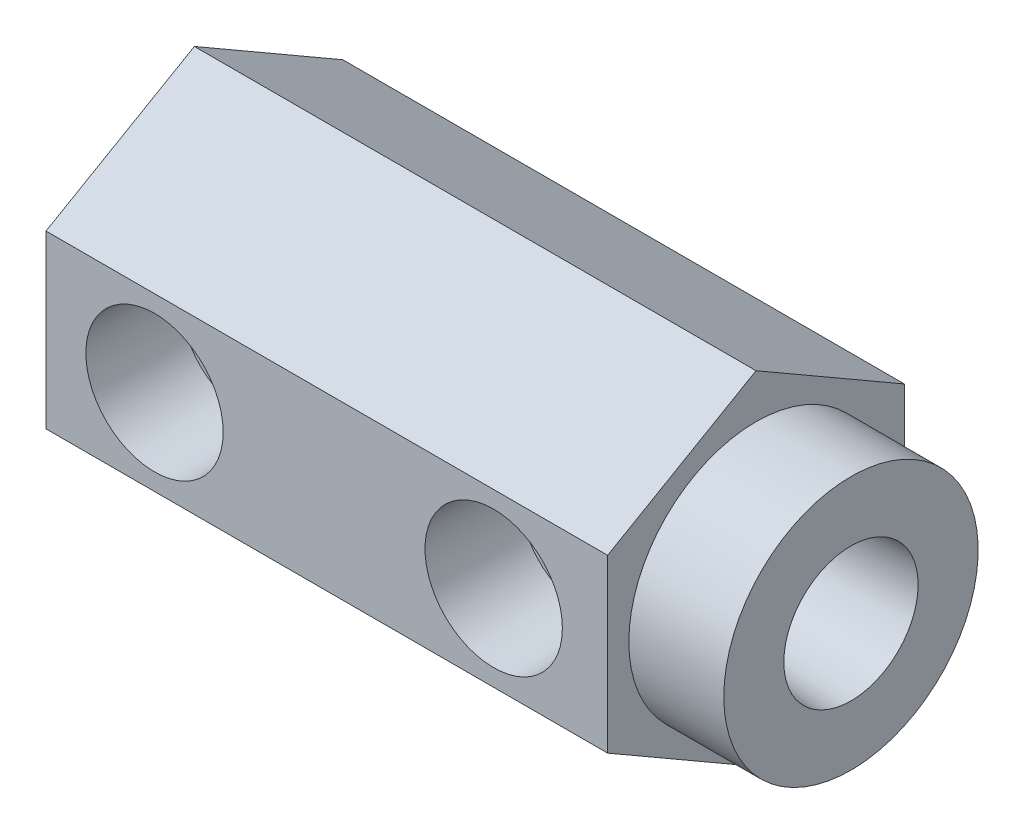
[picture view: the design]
ISO-10303-21;
HEADER;
FILE_DESCRIPTION(('STEP AP214'),'2;1');
FILE_NAME('part.step','',(''),(''),'','','');
FILE_SCHEMA(('AUTOMOTIVE_DESIGN { 1 0 10303 214 1 1 1 1 }'));
ENDSEC;
DATA;
#1=APPLICATION_CONTEXT('core data for automotive mechanical design processes');
#2=APPLICATION_PROTOCOL_DEFINITION('international standard','automotive_design',2000,#1);
#3=PRODUCT_CONTEXT('',#1,'mechanical');
#4=PRODUCT('Part','Part','',(#3));
#5=PRODUCT_RELATED_PRODUCT_CATEGORY('part','',(#4));
#6=PRODUCT_DEFINITION_FORMATION('','',#4);
#7=PRODUCT_DEFINITION_CONTEXT('part definition',#1,'design');
#8=PRODUCT_DEFINITION('design','',#6,#7);
#9=PRODUCT_DEFINITION_SHAPE('','',#8);
#10=(LENGTH_UNIT() NAMED_UNIT(*) SI_UNIT(.MILLI.,.METRE.));
#11=(NAMED_UNIT(*) PLANE_ANGLE_UNIT() SI_UNIT($,.RADIAN.));
#12=(NAMED_UNIT(*) SI_UNIT($,.STERADIAN.) SOLID_ANGLE_UNIT());
#13=UNCERTAINTY_MEASURE_WITH_UNIT(LENGTH_MEASURE(1.E-05),#10,'distance_accuracy_value','');
#14=(GEOMETRIC_REPRESENTATION_CONTEXT(3) GLOBAL_UNCERTAINTY_ASSIGNED_CONTEXT((#13)) GLOBAL_UNIT_ASSIGNED_CONTEXT((#10,
#11,#12)) REPRESENTATION_CONTEXT('',''));
#15=CARTESIAN_POINT('',(0.,0.,0.));
#16=DIRECTION('',(0.,0.,1.));
#17=DIRECTION('',(1.,0.,0.));
#18=AXIS2_PLACEMENT_3D('',#15,#16,#17);
#19=CARTESIAN_POINT('',(49.1744,0.,0.));
#20=DIRECTION('',(-1.,0.,0.));
#21=DIRECTION('',(0.,0.,1.));
#22=AXIS2_PLACEMENT_3D('',#19,#20,#21);
#23=PLANE('',#22);
#24=CARTESIAN_POINT('',(49.1744,0.,0.));
#25=DIRECTION('',(-1.,0.,0.));
#26=DIRECTION('',(0.,0.,1.));
#27=AXIS2_PLACEMENT_3D('',#24,#25,#26);
#28=CIRCLE('',#27,9.525);
#29=CARTESIAN_POINT('',(49.1744,0.,9.525));
#30=VERTEX_POINT('',#29);
#31=EDGE_CURVE('E140',#30,#30,#28,.T.);
#32=ORIENTED_EDGE('',*,*,#31,.F.);
#33=EDGE_LOOP('',(#32));
#34=FACE_BOUND('',#33,.T.);
#35=CARTESIAN_POINT('',(49.1744,0.,0.));
#36=DIRECTION('',(-1.,0.,0.));
#37=DIRECTION('',(0.,0.,1.));
#38=AXIS2_PLACEMENT_3D('',#35,#36,#37);
#39=CIRCLE('',#38,5.0292);
#40=CARTESIAN_POINT('',(49.1744,0.,5.0292));
#41=VERTEX_POINT('',#40);
#42=EDGE_CURVE('E165',#41,#41,#39,.T.);
#43=ORIENTED_EDGE('',*,*,#42,.T.);
#44=EDGE_LOOP('',(#43));
#45=FACE_BOUND('',#44,.T.);
#46=ADVANCED_FACE('F34',(#34,#45),#23,.F.);
#47=CARTESIAN_POINT('',(33.528,0.,11.1125));
#48=DIRECTION('',(0.,0.,1.));
#49=DIRECTION('',(1.,0.,0.));
#50=AXIS2_PLACEMENT_3D('',#47,#48,#49);
#51=CYLINDRICAL_SURFACE('',#50,4.2164);
#52=CARTESIAN_POINT('',(37.5572446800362,1.24226256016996,4.18846));
#53=CARTESIAN_POINT('',(37.5231998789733,1.35273524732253,4.15571145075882));
#54=CARTESIAN_POINT('',(37.4849506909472,1.46061657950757,4.11894514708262));
#55=CARTESIAN_POINT('',(37.4010204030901,1.67046449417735,4.03838194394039));
#56=CARTESIAN_POINT('',(37.3553534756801,1.77244186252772,3.99459845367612));
#57=CARTESIAN_POINT('',(37.2579636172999,1.96909195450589,3.90138657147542));
#58=CARTESIAN_POINT('',(37.2063122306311,2.06383226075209,3.85202501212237));
#59=CARTESIAN_POINT('',(37.0973370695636,2.24704879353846,3.74810382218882));
#60=CARTESIAN_POINT('',(37.040010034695,2.33552136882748,3.69354120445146));
#61=CARTESIAN_POINT('',(36.9057433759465,2.52699524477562,3.56608812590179));
#62=CARTESIAN_POINT('',(36.8274426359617,2.62823562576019,3.49198535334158));
#63=CARTESIAN_POINT('',(36.6643644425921,2.82084714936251,3.33832581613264));
#64=CARTESIAN_POINT('',(36.5795859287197,2.91221667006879,3.25876815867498));
#65=CARTESIAN_POINT('',(36.4040104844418,3.08575940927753,3.09496594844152));
#66=CARTESIAN_POINT('',(36.313183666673,3.16788058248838,3.01069851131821));
#67=CARTESIAN_POINT('',(36.1266289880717,3.32262611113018,2.83900033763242));
#68=CARTESIAN_POINT('',(36.0309017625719,3.39525169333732,2.75157001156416));
#69=CARTESIAN_POINT('',(35.8327510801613,3.53285031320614,2.57262594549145));
#70=CARTESIAN_POINT('',(35.7302251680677,3.59761324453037,2.48106457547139));
#71=CARTESIAN_POINT('',(35.5205770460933,3.7178327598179,2.29700025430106));
#72=CARTESIAN_POINT('',(35.413452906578,3.77328538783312,2.2044969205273));
#73=CARTESIAN_POINT('',(35.1946305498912,3.87490518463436,2.02052791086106));
#74=CARTESIAN_POINT('',(35.0829462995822,3.9210984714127,1.92906002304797));
#75=CARTESIAN_POINT('',(34.8537235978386,4.00442086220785,1.74949909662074));
#76=CARTESIAN_POINT('',(34.7361912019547,4.04155911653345,1.66140272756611));
#77=CARTESIAN_POINT('',(34.5288880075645,4.09683754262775,1.51866750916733));
#78=CARTESIAN_POINT('',(34.4412500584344,4.11734344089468,1.46186744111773));
#79=CARTESIAN_POINT('',(34.2602263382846,4.15335926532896,1.35613372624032));
#80=CARTESIAN_POINT('',(34.166846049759,4.16887387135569,1.30719273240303));
#81=CARTESIAN_POINT('',(34.0032271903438,4.19006857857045,1.23719318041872));
#82=CARTESIAN_POINT('',(33.9349286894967,4.19730703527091,1.21220489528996));
#83=CARTESIAN_POINT('',(33.7951867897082,4.20850549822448,1.17274151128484));
#84=CARTESIAN_POINT('',(33.7237554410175,4.21247707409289,1.15822933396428));
#85=CARTESIAN_POINT('',(33.5783648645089,4.21673052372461,1.14266473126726));
#86=CARTESIAN_POINT('',(33.5043857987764,4.21696850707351,1.14177241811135));
#87=CARTESIAN_POINT('',(33.3576831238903,4.21360126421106,1.15412545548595));
#88=CARTESIAN_POINT('',(33.2849618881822,4.20998943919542,1.16739508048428));
#89=CARTESIAN_POINT('',(33.1190041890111,4.19759986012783,1.21128529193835));
#90=CARTESIAN_POINT('',(33.0270782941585,4.187494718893,1.24623585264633));
#91=CARTESIAN_POINT('',(32.8490963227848,4.16236327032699,1.32777375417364));
#92=CARTESIAN_POINT('',(32.7630740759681,4.14731106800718,1.37442201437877));
#93=CARTESIAN_POINT('',(32.5528728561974,4.10412945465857,1.49961321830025));
#94=CARTESIAN_POINT('',(32.4317509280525,4.07325238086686,1.58224397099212));
#95=CARTESIAN_POINT('',(32.1964925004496,4.00252087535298,1.75355286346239));
#96=CARTESIAN_POINT('',(32.082370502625,3.96264855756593,1.8422428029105));
#97=CARTESIAN_POINT('',(31.8591995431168,3.87396052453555,2.02210861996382));
#98=CARTESIAN_POINT('',(31.7501633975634,3.8251236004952,2.11328994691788));
#99=CARTESIAN_POINT('',(31.5367944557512,3.71851194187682,2.29570274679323));
#100=CARTESIAN_POINT('',(31.4324577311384,3.66074485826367,2.38693411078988));
#101=CARTESIAN_POINT('',(31.2217376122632,3.5320493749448,2.57385350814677));
#102=CARTESIAN_POINT('',(31.1156451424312,3.46051807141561,2.66945656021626));
#103=CARTESIAN_POINT('',(30.9087479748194,3.30668578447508,2.85780367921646));
#104=CARTESIAN_POINT('',(30.8079452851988,3.22438075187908,2.95054665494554));
#105=CARTESIAN_POINT('',(30.6125764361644,3.04885609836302,3.13157084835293));
#106=CARTESIAN_POINT('',(30.5179955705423,2.95566377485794,3.21986246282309));
#107=CARTESIAN_POINT('',(30.3358368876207,2.7579369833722,3.39076686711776));
#108=CARTESIAN_POINT('',(30.248259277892,2.65340217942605,3.47337948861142));
#109=CARTESIAN_POINT('',(30.0468993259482,2.38706899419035,3.66401417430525));
#110=CARTESIAN_POINT('',(29.9372028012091,2.21943248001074,3.76846671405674));
#111=CARTESIAN_POINT('',(29.7890253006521,1.95153796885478,3.91000109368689));
#112=CARTESIAN_POINT('',(29.742405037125,1.85961524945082,3.95461240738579));
#113=CARTESIAN_POINT('',(29.6552306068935,1.67047982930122,4.03813946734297));
#114=CARTESIAN_POINT('',(29.6146718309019,1.57327122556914,4.07705954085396));
#115=CARTESIAN_POINT('',(29.5633807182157,1.43577933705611,4.12632709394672));
#116=CARTESIAN_POINT('',(29.5497360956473,1.3975361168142,4.13943898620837));
#117=CARTESIAN_POINT('',(29.5234701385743,1.32038947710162,4.16468855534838));
#118=CARTESIAN_POINT('',(29.510848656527,1.28148615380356,4.17682637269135));
#119=CARTESIAN_POINT('',(29.4987553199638,1.24226256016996,4.18846));
#120=B_SPLINE_CURVE_WITH_KNOTS('',3,(#52,#53,#54,#55,#56,#57,#58,#59,#60,#61,#62,#63,#64,#65,
#66,#67,#68,#69,#70,#71,#72,#73,#74,#75,#76,#77,#78,#79,#80,#81,#82,#83,#84,#85,#86,#87,#88,#89,
#90,#91,#92,#93,#94,#95,#96,#97,#98,#99,#100,#101,#102,#103,#104,#105,#106,#107,#108,#109,#110,
#111,#112,#113,#114,#115,#116,#117,#118,#119),.UNSPECIFIED.,.F.,.F.,(4,2,2,2,2,2,2,2,2,2,2,2,2,
2,2,2,2,2,2,2,2,2,2,2,2,2,2,2,2,2,2,2,2,4),(0.,0.360139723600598,0.719599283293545,
1.07513522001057,1.43087659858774,1.87389656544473,2.31698921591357,2.76246242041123,
3.2078780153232,3.6633626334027,4.11904029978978,4.57341395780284,5.02732654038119,
5.34631244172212,5.66499838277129,5.88362011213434,6.10146422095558,6.32186731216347,
6.54264879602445,6.83756415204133,7.13404848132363,7.58258817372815,8.03202772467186,
8.48254461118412,8.93267763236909,9.41140117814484,9.89030516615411,10.3680331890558,
10.8457753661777,11.5205176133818,11.8571135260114,12.1934521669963,12.3214366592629,
12.4494026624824),.UNSPECIFIED.);
#121=CARTESIAN_POINT('',(37.5572446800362,1.24226256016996,4.18846));
#122=VERTEX_POINT('',#121);
#123=CARTESIAN_POINT('',(29.4987553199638,1.24226256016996,4.18846));
#124=VERTEX_POINT('',#123);
#125=EDGE_CURVE('E195',#122,#124,#120,.T.);
#126=ORIENTED_EDGE('',*,*,#125,.F.);
#127=CARTESIAN_POINT('',(33.528,0.,4.18846));
#128=DIRECTION('',(0.,0.,1.));
#129=DIRECTION('',(1.,0.,0.));
#130=AXIS2_PLACEMENT_3D('',#127,#128,#129);
#131=CIRCLE('',#130,4.2164);
#132=EDGE_CURVE('E266',#122,#124,#131,.T.);
#133=ORIENTED_EDGE('',*,*,#132,.T.);
#134=EDGE_LOOP('',(#126,#133));
#135=FACE_BOUND('',#134,.T.);
#136=ADVANCED_FACE('F204',(#135),#51,.F.);
#137=CARTESIAN_POINT('',(29.4987553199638,-1.24226256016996,4.18846));
#138=CARTESIAN_POINT('',(29.5328001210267,-1.35273524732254,4.15571145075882));
#139=CARTESIAN_POINT('',(29.5710493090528,-1.46061657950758,4.11894514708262));
#140=CARTESIAN_POINT('',(29.6549795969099,-1.67046449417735,4.03838194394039));
#141=CARTESIAN_POINT('',(29.7006465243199,-1.77244186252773,3.99459845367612));
#142=CARTESIAN_POINT('',(29.7980363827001,-1.96909195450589,3.90138657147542));
#143=CARTESIAN_POINT('',(29.8496877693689,-2.0638322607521,3.85202501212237));
#144=CARTESIAN_POINT('',(29.9586629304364,-2.24704879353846,3.74810382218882));
#145=CARTESIAN_POINT('',(30.015989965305,-2.33552136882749,3.69354120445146));
#146=CARTESIAN_POINT('',(30.1502566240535,-2.52699524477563,3.56608812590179));
#147=CARTESIAN_POINT('',(30.2285573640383,-2.6282356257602,3.49198535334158));
#148=CARTESIAN_POINT('',(30.3916355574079,-2.82084714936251,3.33832581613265));
#149=CARTESIAN_POINT('',(30.4764140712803,-2.9122166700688,3.25876815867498));
#150=CARTESIAN_POINT('',(30.6519895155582,-3.08575940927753,3.09496594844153));
#151=CARTESIAN_POINT('',(30.742816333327,-3.16788058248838,3.01069851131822));
#152=CARTESIAN_POINT('',(30.9293710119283,-3.32262611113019,2.83900033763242));
#153=CARTESIAN_POINT('',(31.0250982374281,-3.39525169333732,2.75157001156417));
#154=CARTESIAN_POINT('',(31.2232489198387,-3.53285031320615,2.57262594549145));
#155=CARTESIAN_POINT('',(31.3257748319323,-3.59761324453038,2.48106457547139));
#156=CARTESIAN_POINT('',(31.5354229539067,-3.7178327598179,2.29700025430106));
#157=CARTESIAN_POINT('',(31.642547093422,-3.77328538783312,2.2044969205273));
#158=CARTESIAN_POINT('',(31.8613694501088,-3.87490518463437,2.02052791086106));
#159=CARTESIAN_POINT('',(31.9730537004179,-3.9210984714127,1.92906002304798));
#160=CARTESIAN_POINT('',(32.2022764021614,-4.00442086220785,1.74949909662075));
#161=CARTESIAN_POINT('',(32.3198087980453,-4.04155911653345,1.66140272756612));
#162=CARTESIAN_POINT('',(32.5271119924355,-4.09683754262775,1.51866750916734));
#163=CARTESIAN_POINT('',(32.6147499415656,-4.11734344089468,1.46186744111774));
#164=CARTESIAN_POINT('',(32.7957736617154,-4.15335926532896,1.35613372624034));
#165=CARTESIAN_POINT('',(32.889153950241,-4.16887387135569,1.30719273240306));
#166=CARTESIAN_POINT('',(33.0527728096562,-4.19006857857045,1.23719318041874));
#167=CARTESIAN_POINT('',(33.1210713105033,-4.19730703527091,1.21220489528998));
#168=CARTESIAN_POINT('',(33.2608132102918,-4.20850549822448,1.17274151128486));
#169=CARTESIAN_POINT('',(33.3322445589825,-4.21247707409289,1.15822933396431));
#170=CARTESIAN_POINT('',(33.4776351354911,-4.21673052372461,1.14266473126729));
#171=CARTESIAN_POINT('',(33.5516142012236,-4.21696850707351,1.14177241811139));
#172=CARTESIAN_POINT('',(33.6983168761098,-4.21360126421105,1.15412545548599));
#173=CARTESIAN_POINT('',(33.7710381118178,-4.20998943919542,1.16739508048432));
#174=CARTESIAN_POINT('',(33.9369958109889,-4.19759986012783,1.21128529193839));
#175=CARTESIAN_POINT('',(34.0289217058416,-4.187494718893,1.24623585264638));
#176=CARTESIAN_POINT('',(34.2069036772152,-4.16236327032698,1.3277737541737));
#177=CARTESIAN_POINT('',(34.292925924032,-4.14731106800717,1.37442201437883));
#178=CARTESIAN_POINT('',(34.5031271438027,-4.10412945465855,1.49961321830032));
#179=CARTESIAN_POINT('',(34.6242490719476,-4.07325238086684,1.5822439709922));
#180=CARTESIAN_POINT('',(34.8595074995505,-4.00252087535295,1.75355286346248));
#181=CARTESIAN_POINT('',(34.9736294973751,-3.9626485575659,1.8422428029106));
#182=CARTESIAN_POINT('',(35.1968004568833,-3.8739605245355,2.02210861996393));
#183=CARTESIAN_POINT('',(35.3058366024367,-3.82512360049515,2.11328994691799));
#184=CARTESIAN_POINT('',(35.5192055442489,-3.71851194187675,2.29570274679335));
#185=CARTESIAN_POINT('',(35.6235422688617,-3.6607448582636,2.38693411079));
#186=CARTESIAN_POINT('',(35.8342623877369,-3.53204937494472,2.5738535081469));
#187=CARTESIAN_POINT('',(35.940354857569,-3.46051807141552,2.66945656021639));
#188=CARTESIAN_POINT('',(36.1472520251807,-3.30668578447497,2.85780367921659));
#189=CARTESIAN_POINT('',(36.2480547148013,-3.22438075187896,2.95054665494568));
#190=CARTESIAN_POINT('',(36.4434235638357,-3.04885609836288,3.13157084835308));
#191=CARTESIAN_POINT('',(36.5380044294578,-2.95566377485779,3.21986246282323));
#192=CARTESIAN_POINT('',(36.7201631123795,-2.75793698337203,3.3907668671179));
#193=CARTESIAN_POINT('',(36.8077407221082,-2.65340217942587,3.47337948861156));
#194=CARTESIAN_POINT('',(37.0091006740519,-2.38706899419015,3.66401417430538));
#195=CARTESIAN_POINT('',(37.118797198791,-2.21943248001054,3.76846671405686));
#196=CARTESIAN_POINT('',(37.2669746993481,-1.95153796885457,3.910001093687));
#197=CARTESIAN_POINT('',(37.3135949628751,-1.85961524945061,3.95461240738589));
#198=CARTESIAN_POINT('',(37.4007693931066,-1.67047982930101,4.03813946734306));
#199=CARTESIAN_POINT('',(37.4413281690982,-1.57327122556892,4.07705954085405));
#200=CARTESIAN_POINT('',(37.4926192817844,-1.43577933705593,4.12632709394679));
#201=CARTESIAN_POINT('',(37.5062639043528,-1.39753611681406,4.13943898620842));
#202=CARTESIAN_POINT('',(37.5325298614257,-1.32038947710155,4.1646885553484));
#203=CARTESIAN_POINT('',(37.545151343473,-1.28148615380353,4.17682637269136));
#204=CARTESIAN_POINT('',(37.5572446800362,-1.24226256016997,4.18846));
#205=B_SPLINE_CURVE_WITH_KNOTS('',3,(#137,#138,#139,#140,#141,#142,#143,#144,#145,#146,#147,
#148,#149,#150,#151,#152,#153,#154,#155,#156,#157,#158,#159,#160,#161,#162,#163,#164,#165,#166,
#167,#168,#169,#170,#171,#172,#173,#174,#175,#176,#177,#178,#179,#180,#181,#182,#183,#184,#185,
#186,#187,#188,#189,#190,#191,#192,#193,#194,#195,#196,#197,#198,#199,#200,#201,#202,#203,#204),
.UNSPECIFIED.,.F.,.F.,(4,2,2,2,2,2,2,2,2,2,2,2,2,2,2,2,2,2,2,2,2,2,2,2,2,2,2,2,2,2,2,2,2,4),(0.,
0.360139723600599,0.719599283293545,1.07513522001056,1.43087659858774,1.87389656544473,
2.31698921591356,2.76246242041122,3.2078780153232,3.6633626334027,4.11904029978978,
4.57341395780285,5.02732654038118,5.34631244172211,5.66499838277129,5.88362011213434,
6.10146422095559,6.32186731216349,6.54264879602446,6.83756415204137,7.13404848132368,
7.58258817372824,8.03202772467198,8.48254461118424,8.93267763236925,9.41140117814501,
9.89030516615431,10.3680331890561,10.8457753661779,11.520517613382,11.8571135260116,
12.1934521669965,12.321436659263,12.4494026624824),.UNSPECIFIED.);
#206=CARTESIAN_POINT('',(29.4987553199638,-1.24226256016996,4.18846));
#207=VERTEX_POINT('',#206);
#208=CARTESIAN_POINT('',(37.5572446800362,-1.24226256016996,4.18846));
#209=VERTEX_POINT('',#208);
#210=EDGE_CURVE('E188',#207,#209,#205,.T.);
#211=ORIENTED_EDGE('',*,*,#210,.F.);
#212=EDGE_CURVE('E269',#207,#209,#131,.T.);
#213=ORIENTED_EDGE('',*,*,#212,.T.);
#214=EDGE_LOOP('',(#211,#213));
#215=FACE_BOUND('',#214,.T.);
#216=ADVANCED_FACE('F208',(#215),#51,.F.);
#217=CARTESIAN_POINT('',(37.7444,0.,4.18846));
#218=DIRECTION('',(0.,0.,-1.));
#219=DIRECTION('',(-1.,0.,0.));
#220=AXIS2_PLACEMENT_3D('',#217,#218,#219);
#221=PLANE('',#220);
#222=DIRECTION('',(-1.,0.,0.));
#223=VECTOR('',#222,1.);
#224=CARTESIAN_POINT('',(0.,-1.24226256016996,4.18846));
#225=LINE('',#224,#223);
#226=CARTESIAN_POINT('',(28.7506884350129,-1.24226256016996,4.18846));
#227=VERTEX_POINT('',#226);
#228=EDGE_CURVE('E355',#227,#207,#225,.F.);
#229=ORIENTED_EDGE('',*,*,#228,.F.);
#230=CARTESIAN_POINT('',(33.528,0.,4.18846));
#231=DIRECTION('',(0.,0.,1.));
#232=DIRECTION('',(1.,0.,0.));
#233=AXIS2_PLACEMENT_3D('',#230,#231,#232);
#234=CIRCLE('',#233,4.93618496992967);
#235=CARTESIAN_POINT('',(38.3053115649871,-1.24226256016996,4.18846));
#236=VERTEX_POINT('',#235);
#237=EDGE_CURVE('E273',#227,#236,#234,.T.);
#238=ORIENTED_EDGE('',*,*,#237,.T.);
#239=EDGE_CURVE('E352',#209,#236,#225,.F.);
#240=ORIENTED_EDGE('',*,*,#239,.F.);
#241=ORIENTED_EDGE('',*,*,#212,.F.);
#242=EDGE_LOOP('',(#229,#238,#240,#241));
#243=FACE_BOUND('',#242,.T.);
#244=ADVANCED_FACE('F211',(#243),#221,.F.);
#245=DIRECTION('',(-1.,0.,0.));
#246=VECTOR('',#245,1.);
#247=CARTESIAN_POINT('',(0.,1.24226256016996,4.18846));
#248=LINE('',#247,#246);
#249=CARTESIAN_POINT('',(38.3053115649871,1.24226256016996,4.18846));
#250=VERTEX_POINT('',#249);
#251=EDGE_CURVE('E199',#250,#122,#248,.T.);
#252=ORIENTED_EDGE('',*,*,#251,.F.);
#253=CARTESIAN_POINT('',(28.7506884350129,1.24226256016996,4.18846));
#254=VERTEX_POINT('',#253);
#255=EDGE_CURVE('E270',#250,#254,#234,.T.);
#256=ORIENTED_EDGE('',*,*,#255,.T.);
#257=EDGE_CURVE('E54',#124,#254,#248,.T.);
#258=ORIENTED_EDGE('',*,*,#257,.F.);
#259=ORIENTED_EDGE('',*,*,#132,.F.);
#260=EDGE_LOOP('',(#252,#256,#258,#259));
#261=FACE_BOUND('',#260,.T.);
#262=ADVANCED_FACE('F336',(#261),#221,.F.);
#263=CARTESIAN_POINT('',(33.528,0.,11.1125));
#264=DIRECTION('',(0.,0.,1.));
#265=DIRECTION('',(1.,0.,0.));
#266=AXIS2_PLACEMENT_3D('',#263,#264,#265);
#267=CONICAL_SURFACE('',#266,5.1435,0.0299323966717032);
#268=CARTESIAN_POINT('',(33.528,0.,11.1125));
#269=DIRECTION('',(0.,0.,1.));
#270=DIRECTION('',(1.,0.,0.));
#271=AXIS2_PLACEMENT_3D('',#268,#269,#270);
#272=CIRCLE('',#271,5.1435);
#273=CARTESIAN_POINT('',(38.6715,0.,11.1125));
#274=VERTEX_POINT('',#273);
#275=EDGE_CURVE('E274',#274,#274,#272,.T.);
#276=ORIENTED_EDGE('',*,*,#275,.T.);
#277=EDGE_LOOP('',(#276));
#278=FACE_BOUND('',#277,.T.);
#279=CARTESIAN_POINT('',(38.3051300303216,-1.24293668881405,4.18826));
#280=CARTESIAN_POINT('',(38.3286071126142,-1.15583523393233,4.21412336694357));
#281=CARTESIAN_POINT('',(38.3497868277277,-1.06732839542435,4.23741836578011));
#282=CARTESIAN_POINT('',(38.3872560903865,-0.888007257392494,4.27858516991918));
#283=CARTESIAN_POINT('',(38.4035434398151,-0.797191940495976,4.29645453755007));
#284=CARTESIAN_POINT('',(38.4309049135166,-0.613876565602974,4.32645329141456));
#285=CARTESIAN_POINT('',(38.4419813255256,-0.521377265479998,4.33858519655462));
#286=CARTESIAN_POINT('',(38.4587218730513,-0.335324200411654,4.35691457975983));
#287=CARTESIAN_POINT('',(38.4643871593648,-0.241770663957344,4.36311331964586));
#288=CARTESIAN_POINT('',(38.4702050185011,-0.0540097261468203,4.36947895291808));
#289=CARTESIAN_POINT('',(38.470341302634,0.0401987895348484,4.36962802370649));
#290=CARTESIAN_POINT('',(38.4650571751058,0.22827319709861,4.36384645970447));
#291=CARTESIAN_POINT('',(38.459636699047,0.322139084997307,4.35791575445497));
#292=CARTESIAN_POINT('',(38.4433617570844,0.508659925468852,4.34009705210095));
#293=CARTESIAN_POINT('',(38.4325165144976,0.601316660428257,4.32821916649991));
#294=CARTESIAN_POINT('',(38.4056075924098,0.784900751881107,4.29871858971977));
#295=CARTESIAN_POINT('',(38.3895464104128,0.875828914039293,4.28109864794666));
#296=CARTESIAN_POINT('',(38.3613463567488,1.01252796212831,4.25011977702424));
#297=CARTESIAN_POINT('',(38.3509951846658,1.05913454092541,4.23874207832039));
#298=CARTESIAN_POINT('',(38.3290123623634,1.15159574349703,4.21456055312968));
#299=CARTESIAN_POINT('',(38.3173825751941,1.19745135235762,4.20175880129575));
#300=CARTESIAN_POINT('',(38.3051300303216,1.24293668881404,4.18826));
#301=B_SPLINE_CURVE_WITH_KNOTS('',3,(#279,#280,#281,#282,#283,#284,#285,#286,#287,#288,#289,
#290,#291,#292,#293,#294,#295,#296,#297,#298,#299,#300),.UNSPECIFIED.,.F.,.F.,(4,2,2,2,2,2,2,2,
2,2,4),(0.,0.281492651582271,0.563111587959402,0.844606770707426,1.12604207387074,
1.40830643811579,1.69057407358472,1.97236341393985,2.25401802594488,2.40121826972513,
2.54820680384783),.UNSPECIFIED.);
#302=EDGE_CURVE('E11',#236,#250,#301,.T.);
#303=ORIENTED_EDGE('',*,*,#302,.F.);
#304=ORIENTED_EDGE('',*,*,#237,.F.);
#305=CARTESIAN_POINT('',(28.7508699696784,1.24293668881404,4.18826));
#306=CARTESIAN_POINT('',(28.7273928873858,1.15583523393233,4.21412336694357));
#307=CARTESIAN_POINT('',(28.7062131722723,1.06732839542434,4.23741836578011));
#308=CARTESIAN_POINT('',(28.6687439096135,0.888007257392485,4.27858516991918));
#309=CARTESIAN_POINT('',(28.6524565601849,0.797191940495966,4.29645453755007));
#310=CARTESIAN_POINT('',(28.6250950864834,0.613876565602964,4.32645329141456));
#311=CARTESIAN_POINT('',(28.6140186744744,0.521377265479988,4.33858519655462));
#312=CARTESIAN_POINT('',(28.5972781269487,0.335324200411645,4.35691457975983));
#313=CARTESIAN_POINT('',(28.5916128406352,0.241770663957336,4.36311331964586));
#314=CARTESIAN_POINT('',(28.5857949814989,0.0540097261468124,4.36947895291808));
#315=CARTESIAN_POINT('',(28.585658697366,-0.0401987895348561,4.36962802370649));
#316=CARTESIAN_POINT('',(28.5909428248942,-0.228273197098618,4.36384645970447));
#317=CARTESIAN_POINT('',(28.596363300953,-0.322139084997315,4.35791575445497));
#318=CARTESIAN_POINT('',(28.6126382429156,-0.50865992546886,4.34009705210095));
#319=CARTESIAN_POINT('',(28.6234834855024,-0.601316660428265,4.32821916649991));
#320=CARTESIAN_POINT('',(28.6503924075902,-0.784900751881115,4.29871858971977));
#321=CARTESIAN_POINT('',(28.6664535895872,-0.875828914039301,4.28109864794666));
#322=CARTESIAN_POINT('',(28.6946536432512,-1.01252796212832,4.25011977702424));
#323=CARTESIAN_POINT('',(28.7050048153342,-1.05913454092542,4.23874207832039));
#324=CARTESIAN_POINT('',(28.7269876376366,-1.15159574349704,4.21456055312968));
#325=CARTESIAN_POINT('',(28.738617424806,-1.19745135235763,4.20175880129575));
#326=CARTESIAN_POINT('',(28.7508699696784,-1.24293668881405,4.18826));
#327=B_SPLINE_CURVE_WITH_KNOTS('',3,(#305,#306,#307,#308,#309,#310,#311,#312,#313,#314,#315,
#316,#317,#318,#319,#320,#321,#322,#323,#324,#325,#326),.UNSPECIFIED.,.F.,.F.,(4,2,2,2,2,2,2,2,
2,2,4),(0.,0.281492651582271,0.563111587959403,0.844606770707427,1.12604207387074,
1.40830643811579,1.69057407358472,1.97236341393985,2.25401802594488,2.40121826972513,
2.54820680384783),.UNSPECIFIED.);
#328=EDGE_CURVE('E47',#254,#227,#327,.T.);
#329=ORIENTED_EDGE('',*,*,#328,.F.);
#330=ORIENTED_EDGE('',*,*,#255,.F.);
#331=EDGE_LOOP('',(#303,#304,#329,#330));
#332=FACE_BOUND('',#331,.T.);
#333=ADVANCED_FACE('F169',(#278,#332),#267,.F.);
#334=CARTESIAN_POINT('',(49.1744,0.,0.));
#335=DIRECTION('',(1.,0.,0.));
#336=DIRECTION('',(0.,0.,-1.));
#337=AXIS2_PLACEMENT_3D('',#334,#335,#336);
#338=CYLINDRICAL_SURFACE('',#337,2.38124999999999);
#339=CARTESIAN_POINT('',(20.5994,0.,0.));
#340=DIRECTION('',(1.,0.,0.));
#341=DIRECTION('',(0.,0.,-1.));
#342=AXIS2_PLACEMENT_3D('',#339,#340,#341);
#343=CIRCLE('',#342,2.38124999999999);
#344=CARTESIAN_POINT('',(20.5994,0.,-2.38124999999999));
#345=VERTEX_POINT('',#344);
#346=EDGE_CURVE('E162',#345,#345,#343,.T.);
#347=ORIENTED_EDGE('',*,*,#346,.F.);
#348=EDGE_LOOP('',(#347));
#349=FACE_BOUND('',#348,.T.);
#350=CARTESIAN_POINT('',(26.9494,0.,0.));
#351=DIRECTION('',(1.,0.,0.));
#352=DIRECTION('',(0.,0.,-1.));
#353=AXIS2_PLACEMENT_3D('',#350,#351,#352);
#354=CIRCLE('',#353,2.38124999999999);
#355=CARTESIAN_POINT('',(26.9494,0.,-2.38124999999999));
#356=VERTEX_POINT('',#355);
#357=EDGE_CURVE('E163',#356,#356,#354,.F.);
#358=ORIENTED_EDGE('',*,*,#357,.F.);
#359=EDGE_LOOP('',(#358));
#360=FACE_BOUND('',#359,.T.);
#361=ADVANCED_FACE('F249',(#349,#360),#338,.F.);
#362=CARTESIAN_POINT('',(42.0624,6.41580486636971,11.1125));
#363=DIRECTION('',(0.,0.,-1.));
#364=DIRECTION('',(0.,1.,0.));
#365=AXIS2_PLACEMENT_3D('',#362,#363,#364);
#366=PLANE('',#365);
#367=CARTESIAN_POINT('',(8.128,0.,11.1125));
#368=DIRECTION('',(0.,0.,1.));
#369=DIRECTION('',(1.,0.,0.));
#370=AXIS2_PLACEMENT_3D('',#367,#368,#369);
#371=CIRCLE('',#370,5.1435);
#372=CARTESIAN_POINT('',(13.2715,0.,11.1125));
#373=VERTEX_POINT('',#372);
#374=EDGE_CURVE('E283',#373,#373,#371,.T.);
#375=ORIENTED_EDGE('',*,*,#374,.F.);
#376=EDGE_LOOP('',(#375));
#377=FACE_BOUND('',#376,.T.);
#378=ORIENTED_EDGE('',*,*,#275,.F.);
#379=EDGE_LOOP('',(#378));
#380=FACE_BOUND('',#379,.T.);
#381=DIRECTION('',(0.,-1.,0.));
#382=VECTOR('',#381,1.);
#383=CARTESIAN_POINT('',(0.,6.41580486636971,11.1125));
#384=LINE('',#383,#382);
#385=CARTESIAN_POINT('',(0.,6.41580486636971,11.1125));
#386=VERTEX_POINT('',#385);
#387=CARTESIAN_POINT('',(0.,-6.41580486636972,11.1125));
#388=VERTEX_POINT('',#387);
#389=EDGE_CURVE('E136',#386,#388,#384,.T.);
#390=ORIENTED_EDGE('',*,*,#389,.T.);
#391=DIRECTION('',(-1.,0.,0.));
#392=VECTOR('',#391,1.);
#393=CARTESIAN_POINT('',(42.0624,-6.41580486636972,11.1125));
#394=LINE('',#393,#392);
#395=CARTESIAN_POINT('',(42.0624,-6.41580486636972,11.1125));
#396=VERTEX_POINT('',#395);
#397=EDGE_CURVE('E155',#396,#388,#394,.T.);
#398=ORIENTED_EDGE('',*,*,#397,.F.);
#399=DIRECTION('',(0.,-1.,0.));
#400=VECTOR('',#399,1.);
#401=CARTESIAN_POINT('',(42.0624,6.41580486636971,11.1125));
#402=LINE('',#401,#400);
#403=CARTESIAN_POINT('',(42.0624,6.41580486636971,11.1125));
#404=VERTEX_POINT('',#403);
#405=EDGE_CURVE('E148',#404,#396,#402,.T.);
#406=ORIENTED_EDGE('',*,*,#405,.F.);
#407=DIRECTION('',(-1.,0.,0.));
#408=VECTOR('',#407,1.);
#409=CARTESIAN_POINT('',(42.0624,6.41580486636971,11.1125));
#410=LINE('',#409,#408);
#411=EDGE_CURVE('E132',#404,#386,#410,.T.);
#412=ORIENTED_EDGE('',*,*,#411,.T.);
#413=EDGE_LOOP('',(#390,#398,#406,#412));
#414=FACE_BOUND('',#413,.T.);
#415=ADVANCED_FACE('F36',(#377,#380,#414),#366,.F.);
#416=CARTESIAN_POINT('',(42.0624,-6.41580486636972,11.1125));
#417=DIRECTION('',(0.,0.866025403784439,-0.5));
#418=DIRECTION('',(0.,0.5,0.866025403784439));
#419=AXIS2_PLACEMENT_3D('',#416,#417,#418);
#420=PLANE('',#419);
#421=DIRECTION('',(0.,-0.5,-0.866025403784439));
#422=VECTOR('',#421,1.);
#423=CARTESIAN_POINT('',(0.,-6.41580486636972,11.1125));
#424=LINE('',#423,#422);
#425=CARTESIAN_POINT('',(0.,-12.8316097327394,0.));
#426=VERTEX_POINT('',#425);
#427=EDGE_CURVE('E139',#388,#426,#424,.T.);
#428=ORIENTED_EDGE('',*,*,#427,.T.);
#429=DIRECTION('',(-1.,0.,0.));
#430=VECTOR('',#429,1.);
#431=CARTESIAN_POINT('',(42.0624,-12.8316097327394,0.));
#432=LINE('',#431,#430);
#433=CARTESIAN_POINT('',(42.0624,-12.8316097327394,0.));
#434=VERTEX_POINT('',#433);
#435=EDGE_CURVE('E152',#434,#426,#432,.T.);
#436=ORIENTED_EDGE('',*,*,#435,.F.);
#437=DIRECTION('',(0.,-0.5,-0.866025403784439));
#438=VECTOR('',#437,1.);
#439=CARTESIAN_POINT('',(42.0624,-6.41580486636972,11.1125));
#440=LINE('',#439,#438);
#441=EDGE_CURVE('E99',#396,#434,#440,.T.);
#442=ORIENTED_EDGE('',*,*,#441,.F.);
#443=ORIENTED_EDGE('',*,*,#397,.T.);
#444=EDGE_LOOP('',(#428,#436,#442,#443));
#445=FACE_BOUND('',#444,.T.);
#446=ADVANCED_FACE('F243',(#445),#420,.F.);
#447=CARTESIAN_POINT('',(42.0624,-12.8316097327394,0.));
#448=DIRECTION('',(0.,0.866025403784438,0.5));
#449=DIRECTION('',(0.,-0.5,0.866025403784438));
#450=AXIS2_PLACEMENT_3D('',#447,#448,#449);
#451=PLANE('',#450);
#452=DIRECTION('',(0.,0.5,-0.866025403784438));
#453=VECTOR('',#452,1.);
#454=CARTESIAN_POINT('',(0.,-12.8316097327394,0.));
#455=LINE('',#454,#453);
#456=CARTESIAN_POINT('',(0.,-6.41580486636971,-11.1125));
#457=VERTEX_POINT('',#456);
#458=EDGE_CURVE('E142',#426,#457,#455,.T.);
#459=ORIENTED_EDGE('',*,*,#458,.T.);
#460=DIRECTION('',(-1.,0.,0.));
#461=VECTOR('',#460,1.);
#462=CARTESIAN_POINT('',(42.0624,-6.41580486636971,-11.1125));
#463=LINE('',#462,#461);
#464=CARTESIAN_POINT('',(42.0624,-6.41580486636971,-11.1125));
#465=VERTEX_POINT('',#464);
#466=EDGE_CURVE('E127',#465,#457,#463,.T.);
#467=ORIENTED_EDGE('',*,*,#466,.F.);
#468=DIRECTION('',(0.,0.5,-0.866025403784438));
#469=VECTOR('',#468,1.);
#470=CARTESIAN_POINT('',(42.0624,-12.8316097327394,0.));
#471=LINE('',#470,#469);
#472=EDGE_CURVE('E115',#434,#465,#471,.T.);
#473=ORIENTED_EDGE('',*,*,#472,.F.);
#474=ORIENTED_EDGE('',*,*,#435,.T.);
#475=EDGE_LOOP('',(#459,#467,#473,#474));
#476=FACE_BOUND('',#475,.T.);
#477=ADVANCED_FACE('F240',(#476),#451,.F.);
#478=CARTESIAN_POINT('',(42.0624,-6.41580486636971,-11.1125));
#479=DIRECTION('',(0.,0.,1.));
#480=DIRECTION('',(1.,0.,0.));
#481=AXIS2_PLACEMENT_3D('',#478,#479,#480);
#482=PLANE('',#481);
#483=CARTESIAN_POINT('',(8.128,0.,-11.1125));
#484=DIRECTION('',(0.,0.,-1.));
#485=DIRECTION('',(-1.,0.,0.));
#486=AXIS2_PLACEMENT_3D('',#483,#484,#485);
#487=CIRCLE('',#486,5.1435);
#488=CARTESIAN_POINT('',(2.9845,0.,-11.1125));
#489=VERTEX_POINT('',#488);
#490=EDGE_CURVE('E292',#489,#489,#487,.T.);
#491=ORIENTED_EDGE('',*,*,#490,.F.);
#492=EDGE_LOOP('',(#491));
#493=FACE_BOUND('',#492,.T.);
#494=DIRECTION('',(0.,1.,0.));
#495=VECTOR('',#494,1.);
#496=CARTESIAN_POINT('',(0.,-6.41580486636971,-11.1125));
#497=LINE('',#496,#495);
#498=CARTESIAN_POINT('',(0.,6.41580486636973,-11.1125));
#499=VERTEX_POINT('',#498);
#500=EDGE_CURVE('E124',#457,#499,#497,.T.);
#501=ORIENTED_EDGE('',*,*,#500,.T.);
#502=DIRECTION('',(-1.,0.,0.));
#503=VECTOR('',#502,1.);
#504=CARTESIAN_POINT('',(42.0624,6.41580486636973,-11.1125));
#505=LINE('',#504,#503);
#506=CARTESIAN_POINT('',(42.0624,6.41580486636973,-11.1125));
#507=VERTEX_POINT('',#506);
#508=EDGE_CURVE('E121',#507,#499,#505,.T.);
#509=ORIENTED_EDGE('',*,*,#508,.F.);
#510=DIRECTION('',(0.,1.,0.));
#511=VECTOR('',#510,1.);
#512=CARTESIAN_POINT('',(42.0624,-6.41580486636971,-11.1125));
#513=LINE('',#512,#511);
#514=EDGE_CURVE('E108',#465,#507,#513,.T.);
#515=ORIENTED_EDGE('',*,*,#514,.F.);
#516=ORIENTED_EDGE('',*,*,#466,.T.);
#517=EDGE_LOOP('',(#501,#509,#515,#516));
#518=FACE_BOUND('',#517,.T.);
#519=ADVANCED_FACE('F122',(#493,#518),#482,.F.);
#520=CARTESIAN_POINT('',(42.0624,6.41580486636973,-11.1125));
#521=DIRECTION('',(0.,-0.866025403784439,0.5));
#522=DIRECTION('',(0.,-0.5,-0.866025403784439));
#523=AXIS2_PLACEMENT_3D('',#520,#521,#522);
#524=PLANE('',#523);
#525=DIRECTION('',(0.,0.5,0.866025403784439));
#526=VECTOR('',#525,1.);
#527=CARTESIAN_POINT('',(0.,6.41580486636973,-11.1125));
#528=LINE('',#527,#526);
#529=CARTESIAN_POINT('',(0.,12.8316097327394,0.));
#530=VERTEX_POINT('',#529);
#531=EDGE_CURVE('E145',#499,#530,#528,.T.);
#532=ORIENTED_EDGE('',*,*,#531,.T.);
#533=DIRECTION('',(-1.,0.,0.));
#534=VECTOR('',#533,1.);
#535=CARTESIAN_POINT('',(42.0624,12.8316097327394,0.));
#536=LINE('',#535,#534);
#537=CARTESIAN_POINT('',(42.0624,12.8316097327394,0.));
#538=VERTEX_POINT('',#537);
#539=EDGE_CURVE('E128',#538,#530,#536,.T.);
#540=ORIENTED_EDGE('',*,*,#539,.F.);
#541=DIRECTION('',(0.,0.5,0.866025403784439));
#542=VECTOR('',#541,1.);
#543=CARTESIAN_POINT('',(42.0624,6.41580486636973,-11.1125));
#544=LINE('',#543,#542);
#545=EDGE_CURVE('E112',#507,#538,#544,.T.);
#546=ORIENTED_EDGE('',*,*,#545,.F.);
#547=ORIENTED_EDGE('',*,*,#508,.T.);
#548=EDGE_LOOP('',(#532,#540,#546,#547));
#549=FACE_BOUND('',#548,.T.);
#550=ADVANCED_FACE('F130',(#549),#524,.F.);
#551=CARTESIAN_POINT('',(42.0624,12.8316097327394,0.));
#552=DIRECTION('',(0.,-0.866025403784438,-0.500000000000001));
#553=DIRECTION('',(0.,0.500000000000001,-0.866025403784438));
#554=AXIS2_PLACEMENT_3D('',#551,#552,#553);
#555=PLANE('',#554);
#556=DIRECTION('',(0.,-0.500000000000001,0.866025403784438));
#557=VECTOR('',#556,1.);
#558=CARTESIAN_POINT('',(0.,12.8316097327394,0.));
#559=LINE('',#558,#557);
#560=EDGE_CURVE('E90',#530,#386,#559,.T.);
#561=ORIENTED_EDGE('',*,*,#560,.T.);
#562=ORIENTED_EDGE('',*,*,#411,.F.);
#563=DIRECTION('',(0.,-0.500000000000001,0.866025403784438));
#564=VECTOR('',#563,1.);
#565=CARTESIAN_POINT('',(42.0624,12.8316097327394,0.));
#566=LINE('',#565,#564);
#567=EDGE_CURVE('E63',#538,#404,#566,.T.);
#568=ORIENTED_EDGE('',*,*,#567,.F.);
#569=ORIENTED_EDGE('',*,*,#539,.T.);
#570=EDGE_LOOP('',(#561,#562,#568,#569));
#571=FACE_BOUND('',#570,.T.);
#572=ADVANCED_FACE('F229',(#571),#555,.F.);
#573=CARTESIAN_POINT('',(42.0624,-6.41580486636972,11.1125));
#574=DIRECTION('',(1.,0.,0.));
#575=DIRECTION('',(0.,0.,-1.));
#576=AXIS2_PLACEMENT_3D('',#573,#574,#575);
#577=PLANE('',#576);
#578=CARTESIAN_POINT('',(42.0624,0.,0.));
#579=DIRECTION('',(1.,0.,0.));
#580=DIRECTION('',(0.,0.,-1.));
#581=AXIS2_PLACEMENT_3D('',#578,#579,#580);
#582=CIRCLE('',#581,9.525);
#583=CARTESIAN_POINT('',(42.0624,0.,-9.525));
#584=VERTEX_POINT('',#583);
#585=EDGE_CURVE('E157',#584,#584,#582,.T.);
#586=ORIENTED_EDGE('',*,*,#585,.F.);
#587=EDGE_LOOP('',(#586));
#588=FACE_BOUND('',#587,.T.);
#589=ORIENTED_EDGE('',*,*,#405,.T.);
#590=ORIENTED_EDGE('',*,*,#441,.T.);
#591=ORIENTED_EDGE('',*,*,#472,.T.);
#592=ORIENTED_EDGE('',*,*,#514,.T.);
#593=ORIENTED_EDGE('',*,*,#545,.T.);
#594=ORIENTED_EDGE('',*,*,#567,.T.);
#595=EDGE_LOOP('',(#589,#590,#591,#592,#593,#594));
#596=FACE_BOUND('',#595,.T.);
#597=ADVANCED_FACE('F110',(#588,#596),#577,.T.);
#598=CARTESIAN_POINT('',(0.,-6.41580486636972,11.1125));
#599=DIRECTION('',(1.,0.,0.));
#600=DIRECTION('',(0.,0.,-1.));
#601=AXIS2_PLACEMENT_3D('',#598,#599,#600);
#602=PLANE('',#601);
#603=ORIENTED_EDGE('',*,*,#389,.F.);
#604=ORIENTED_EDGE('',*,*,#560,.F.);
#605=ORIENTED_EDGE('',*,*,#531,.F.);
#606=ORIENTED_EDGE('',*,*,#500,.F.);
#607=ORIENTED_EDGE('',*,*,#458,.F.);
#608=ORIENTED_EDGE('',*,*,#427,.F.);
#609=EDGE_LOOP('',(#603,#604,#605,#606,#607,#608));
#610=FACE_BOUND('',#609,.T.);
#611=ADVANCED_FACE('F225',(#610),#602,.F.);
#612=CARTESIAN_POINT('',(49.1744,0.,0.));
#613=DIRECTION('',(-1.,0.,0.));
#614=DIRECTION('',(0.,0.,1.));
#615=AXIS2_PLACEMENT_3D('',#612,#613,#614);
#616=CYLINDRICAL_SURFACE('',#615,9.525);
#617=ORIENTED_EDGE('',*,*,#585,.T.);
#618=EDGE_LOOP('',(#617));
#619=FACE_BOUND('',#618,.T.);
#620=ORIENTED_EDGE('',*,*,#31,.T.);
#621=EDGE_LOOP('',(#620));
#622=FACE_BOUND('',#621,.T.);
#623=ADVANCED_FACE('F221',(#619,#622),#616,.T.);
#624=CARTESIAN_POINT('',(8.128,0.,11.1125));
#625=DIRECTION('',(0.,0.,1.));
#626=DIRECTION('',(1.,0.,0.));
#627=AXIS2_PLACEMENT_3D('',#624,#625,#626);
#628=CYLINDRICAL_SURFACE('',#627,4.2164);
#629=CARTESIAN_POINT('',(12.3444,0.,-2.01929999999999));
#630=CARTESIAN_POINT('',(12.3443947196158,0.106687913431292,-2.01929379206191));
#631=CARTESIAN_POINT('',(12.3403065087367,0.213518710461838,-2.01079506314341));
#632=CARTESIAN_POINT('',(12.324356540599,0.424056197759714,-1.97716034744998));
#633=CARTESIAN_POINT('',(12.3124784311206,0.527755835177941,-1.95198936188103));
#634=CARTESIAN_POINT('',(12.2821989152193,0.728658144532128,-1.8862021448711));
#635=CARTESIAN_POINT('',(12.2638221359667,0.825883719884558,-1.84564418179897));
#636=CARTESIAN_POINT('',(12.2222578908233,1.01202231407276,-1.75051924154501));
#637=CARTESIAN_POINT('',(12.1990710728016,1.10093645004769,-1.69595415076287));
#638=CARTESIAN_POINT('',(12.1485066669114,1.27361832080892,-1.57082016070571));
#639=CARTESIAN_POINT('',(12.1209657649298,1.35680605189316,-1.49951775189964));
#640=CARTESIAN_POINT('',(12.0653733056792,1.51056872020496,-1.34450262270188));
#641=CARTESIAN_POINT('',(12.0373214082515,1.58113489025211,-1.26078134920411));
#642=CARTESIAN_POINT('',(11.9816498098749,1.71255866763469,-1.07629586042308));
#643=CARTESIAN_POINT('',(11.9541960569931,1.7723988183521,-0.974751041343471));
#644=CARTESIAN_POINT('',(11.9055283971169,1.87389933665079,-0.761566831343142));
#645=CARTESIAN_POINT('',(11.8843103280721,1.91557183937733,-0.649934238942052));
#646=CARTESIAN_POINT('',(11.8523398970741,1.97698392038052,-0.426331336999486));
#647=CARTESIAN_POINT('',(11.8410563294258,1.99784596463,-0.314748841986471));
#648=CARTESIAN_POINT('',(11.8287790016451,2.02050711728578,-0.0891428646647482));
#649=CARTESIAN_POINT('',(11.8277764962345,2.02232242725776,0.0248784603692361));
#650=CARTESIAN_POINT('',(11.835740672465,2.00766665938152,0.238980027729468));
#651=CARTESIAN_POINT('',(11.843647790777,1.99313940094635,0.339241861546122));
#652=CARTESIAN_POINT('',(11.8667010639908,1.94954991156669,0.535681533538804));
#653=CARTESIAN_POINT('',(11.8818492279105,1.92048364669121,0.631858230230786));
#654=CARTESIAN_POINT('',(11.9180243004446,1.84808217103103,0.820108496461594));
#655=CARTESIAN_POINT('',(11.9391797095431,1.80443089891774,0.912034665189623));
#656=CARTESIAN_POINT('',(11.9849808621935,1.70433373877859,1.08768048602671));
#657=CARTESIAN_POINT('',(12.0096281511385,1.64788217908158,1.17139647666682));
#658=CARTESIAN_POINT('',(12.0630694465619,1.51619938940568,1.33838656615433));
#659=CARTESIAN_POINT('',(12.0920142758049,1.43955472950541,1.42050154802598));
#660=CARTESIAN_POINT('',(12.1484663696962,1.27341129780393,1.57117111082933));
#661=CARTESIAN_POINT('',(12.1759730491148,1.1839073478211,1.63972020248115));
#662=CARTESIAN_POINT('',(12.2277795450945,0.990088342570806,1.76381495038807));
#663=CARTESIAN_POINT('',(12.2519106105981,0.885329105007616,1.81874288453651));
#664=CARTESIAN_POINT('',(12.2928537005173,0.666605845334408,1.90976726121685));
#665=CARTESIAN_POINT('',(12.3096710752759,0.552648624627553,1.94587747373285));
#666=CARTESIAN_POINT('',(12.3329916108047,0.328309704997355,1.99547875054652));
#667=CARTESIAN_POINT('',(12.3401974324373,0.21834329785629,2.01051544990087));
#668=CARTESIAN_POINT('',(12.3458467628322,-0.00277260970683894,2.02232712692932));
#669=CARTESIAN_POINT('',(12.3442939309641,-0.113921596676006,2.01910973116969));
#670=CARTESIAN_POINT('',(12.3330254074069,-0.326023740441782,1.99546315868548));
#671=CARTESIAN_POINT('',(12.3238866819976,-0.427147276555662,1.97625026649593));
#672=CARTESIAN_POINT('',(12.2990742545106,-0.624556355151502,1.92300728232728));
#673=CARTESIAN_POINT('',(12.2833998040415,-0.720841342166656,1.88897549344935));
#674=CARTESIAN_POINT('',(12.2463664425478,-0.909163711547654,1.80607296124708));
#675=CARTESIAN_POINT('',(12.2248507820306,-1.00098632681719,1.75678680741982));
#676=CARTESIAN_POINT('',(12.1782688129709,-1.17537718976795,1.64523197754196));
#677=CARTESIAN_POINT('',(12.1532009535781,-1.25794136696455,1.58295762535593));
#678=CARTESIAN_POINT('',(12.0992710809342,-1.41948396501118,1.44057879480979));
#679=CARTESIAN_POINT('',(12.0702719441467,-1.49743912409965,1.35936289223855));
#680=CARTESIAN_POINT('',(12.013541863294,-1.63903132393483,1.18481538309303));
#681=CARTESIAN_POINT('',(11.9858116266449,-1.70266045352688,1.09147712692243));
#682=CARTESIAN_POINT('',(11.9338112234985,-1.81600503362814,0.890769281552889));
#683=CARTESIAN_POINT('',(11.9097123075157,-1.86510080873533,0.783001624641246));
#684=CARTESIAN_POINT('',(11.8698056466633,-1.94394019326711,0.559196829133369));
#685=CARTESIAN_POINT('',(11.8539881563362,-1.9737065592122,0.443169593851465));
#686=CARTESIAN_POINT('',(11.8342677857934,-2.01047355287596,0.217679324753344));
#687=CARTESIAN_POINT('',(11.8293967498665,-2.01932799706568,0.108604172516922));
#688=CARTESIAN_POINT('',(11.8294288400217,-2.01927189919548,-0.10952351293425));
#689=CARTESIAN_POINT('',(11.8343287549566,-2.01036719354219,-0.218576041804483));
#690=CARTESIAN_POINT('',(11.8523574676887,-1.97674011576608,-0.424338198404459));
#691=CARTESIAN_POINT('',(11.8647906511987,-1.95335151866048,-0.52133390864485));
#692=CARTESIAN_POINT('',(11.8957350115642,-1.89297275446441,-0.709957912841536));
#693=CARTESIAN_POINT('',(11.9142480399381,-1.85597844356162,-0.801584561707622));
#694=CARTESIAN_POINT('',(11.9567879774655,-1.76663819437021,-0.983627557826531));
#695=CARTESIAN_POINT('',(11.9811010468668,-1.71343032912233,-1.07355223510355));
#696=CARTESIAN_POINT('',(12.0319461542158,-1.59418732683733,-1.2437641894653));
#697=CARTESIAN_POINT('',(12.0584792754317,-1.52814590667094,-1.32404671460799));
#698=CARTESIAN_POINT('',(12.1142040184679,-1.37673061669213,-1.48168072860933));
#699=CARTESIAN_POINT('',(12.1433736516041,-1.29003977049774,-1.55778172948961));
#700=CARTESIAN_POINT('',(12.1983964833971,-1.10421108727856,-1.69457937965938));
#701=CARTESIAN_POINT('',(12.2242480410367,-1.00506713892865,-1.75526842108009));
#702=CARTESIAN_POINT('',(12.2697969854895,-0.796801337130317,-1.85908628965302));
#703=CARTESIAN_POINT('',(12.2895022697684,-0.68769252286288,-1.90223767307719));
#704=CARTESIAN_POINT('',(12.3204605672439,-0.462707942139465,-1.96905011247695));
#705=CARTESIAN_POINT('',(12.3317383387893,-0.346853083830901,-1.99276827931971));
#706=CARTESIAN_POINT('',(12.3402176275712,-0.191644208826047,-2.0105538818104));
#707=CARTESIAN_POINT('',(12.3417825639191,-0.15341184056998,-2.01382975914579));
#708=CARTESIAN_POINT('',(12.343874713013,-0.0767924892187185,-2.01820396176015));
#709=CARTESIAN_POINT('',(12.3444019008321,-0.038405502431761,-2.0193022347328));
#710=CARTESIAN_POINT('',(12.3444,0.,-2.01929999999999));
#711=B_SPLINE_CURVE_WITH_KNOTS('',3,(#629,#630,#631,#632,#633,#634,#635,#636,#637,#638,#639,
#640,#641,#642,#643,#644,#645,#646,#647,#648,#649,#650,#651,#652,#653,#654,#655,#656,#657,#658,
#659,#660,#661,#662,#663,#664,#665,#666,#667,#668,#669,#670,#671,#672,#673,#674,#675,#676,#677,
#678,#679,#680,#681,#682,#683,#684,#685,#686,#687,#688,#689,#690,#691,#692,#693,#694,#695,#696,
#697,#698,#699,#700,#701,#702,#703,#704,#705,#706,#707,#708,#709,#710),.UNSPECIFIED.,.T.,.F.,(4,
2,2,2,2,2,2,2,2,2,2,2,2,2,2,2,2,2,2,2,2,2,2,2,2,2,2,2,2,2,2,2,2,2,2,2,2,2,2,2,4),(0.,
0.319907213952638,0.640488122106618,0.959866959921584,1.27920280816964,1.61669430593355,
1.95441932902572,2.31564840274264,2.67663582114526,3.01688536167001,3.35684545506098,
3.66027862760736,3.96379603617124,4.27437070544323,4.58508325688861,4.93154597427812,
5.27814859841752,5.63838803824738,5.99836349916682,6.33023891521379,6.66197568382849,
6.97057174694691,7.27920315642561,7.59711450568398,7.91516508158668,8.26238386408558,
8.6097939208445,8.97038842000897,9.33055761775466,9.65735534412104,9.98404568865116,
10.284385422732,10.5848167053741,10.905360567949,11.2260617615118,11.5813594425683,
11.9368321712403,12.2918462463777,12.6458132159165,12.7609706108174,12.8761307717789),.UNSPECIFIED.);
#712=CARTESIAN_POINT('',(12.3444,0.,-2.01929999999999));
#713=VERTEX_POINT('',#712);
#714=EDGE_CURVE('E161',#713,#713,#711,.T.);
#715=ORIENTED_EDGE('',*,*,#714,.T.);
#716=EDGE_LOOP('',(#715));
#717=FACE_BOUND('',#716,.T.);
#718=CARTESIAN_POINT('',(8.128,0.,-4.18846));
#719=DIRECTION('',(0.,0.,-1.));
#720=DIRECTION('',(-1.,0.,0.));
#721=AXIS2_PLACEMENT_3D('',#718,#719,#720);
#722=CIRCLE('',#721,4.21640000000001);
#723=CARTESIAN_POINT('',(3.91159999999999,0.,-4.18846));
#724=VERTEX_POINT('',#723);
#725=EDGE_CURVE('E286',#724,#724,#722,.T.);
#726=ORIENTED_EDGE('',*,*,#725,.T.);
#727=EDGE_LOOP('',(#726));
#728=FACE_BOUND('',#727,.T.);
#729=CARTESIAN_POINT('',(8.128,0.,4.18846));
#730=DIRECTION('',(0.,0.,1.));
#731=DIRECTION('',(1.,0.,0.));
#732=AXIS2_PLACEMENT_3D('',#729,#730,#731);
#733=CIRCLE('',#732,4.2164);
#734=CARTESIAN_POINT('',(12.3444,0.,4.18846));
#735=VERTEX_POINT('',#734);
#736=EDGE_CURVE('E277',#735,#735,#733,.T.);
#737=ORIENTED_EDGE('',*,*,#736,.T.);
#738=EDGE_LOOP('',(#737));
#739=FACE_BOUND('',#738,.T.);
#740=ADVANCED_FACE('F224',(#717,#728,#739),#628,.F.);
#741=CARTESIAN_POINT('',(12.3444,0.,4.18846));
#742=DIRECTION('',(0.,0.,-1.));
#743=DIRECTION('',(-1.,0.,0.));
#744=AXIS2_PLACEMENT_3D('',#741,#742,#743);
#745=PLANE('',#744);
#746=ORIENTED_EDGE('',*,*,#736,.F.);
#747=EDGE_LOOP('',(#746));
#748=FACE_BOUND('',#747,.T.);
#749=CARTESIAN_POINT('',(8.128,0.,4.18846));
#750=DIRECTION('',(0.,0.,1.));
#751=DIRECTION('',(1.,0.,0.));
#752=AXIS2_PLACEMENT_3D('',#749,#750,#751);
#753=CIRCLE('',#752,4.93618496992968);
#754=CARTESIAN_POINT('',(13.0641849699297,0.,4.18846));
#755=VERTEX_POINT('',#754);
#756=EDGE_CURVE('E280',#755,#755,#753,.T.);
#757=ORIENTED_EDGE('',*,*,#756,.T.);
#758=EDGE_LOOP('',(#757));
#759=FACE_BOUND('',#758,.T.);
#760=ADVANCED_FACE('F318',(#748,#759),#745,.F.);
#761=CARTESIAN_POINT('',(8.128,0.,11.1125));
#762=DIRECTION('',(0.,0.,1.));
#763=DIRECTION('',(1.,0.,0.));
#764=AXIS2_PLACEMENT_3D('',#761,#762,#763);
#765=CONICAL_SURFACE('',#764,5.1435,0.0299323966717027);
#766=ORIENTED_EDGE('',*,*,#756,.F.);
#767=EDGE_LOOP('',(#766));
#768=FACE_BOUND('',#767,.T.);
#769=ORIENTED_EDGE('',*,*,#374,.T.);
#770=EDGE_LOOP('',(#769));
#771=FACE_BOUND('',#770,.T.);
#772=ADVANCED_FACE('F315',(#768,#771),#765,.F.);
#773=CARTESIAN_POINT('',(12.3444,0.,-4.18846));
#774=DIRECTION('',(0.,0.,1.));
#775=DIRECTION('',(1.,0.,0.));
#776=AXIS2_PLACEMENT_3D('',#773,#774,#775);
#777=PLANE('',#776);
#778=ORIENTED_EDGE('',*,*,#725,.F.);
#779=EDGE_LOOP('',(#778));
#780=FACE_BOUND('',#779,.T.);
#781=CARTESIAN_POINT('',(8.128,0.,-4.18846));
#782=DIRECTION('',(0.,0.,-1.));
#783=DIRECTION('',(-1.,0.,0.));
#784=AXIS2_PLACEMENT_3D('',#781,#782,#783);
#785=CIRCLE('',#784,4.93618496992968);
#786=CARTESIAN_POINT('',(3.19181503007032,0.,-4.18846));
#787=VERTEX_POINT('',#786);
#788=EDGE_CURVE('E289',#787,#787,#785,.T.);
#789=ORIENTED_EDGE('',*,*,#788,.T.);
#790=EDGE_LOOP('',(#789));
#791=FACE_BOUND('',#790,.T.);
#792=ADVANCED_FACE('F311',(#780,#791),#777,.F.);
#793=CARTESIAN_POINT('',(8.128,0.,-11.1125));
#794=DIRECTION('',(0.,0.,-1.));
#795=DIRECTION('',(-1.,0.,0.));
#796=AXIS2_PLACEMENT_3D('',#793,#794,#795);
#797=CONICAL_SURFACE('',#796,5.1435,0.0299323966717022);
#798=ORIENTED_EDGE('',*,*,#788,.F.);
#799=EDGE_LOOP('',(#798));
#800=FACE_BOUND('',#799,.T.);
#801=ORIENTED_EDGE('',*,*,#490,.T.);
#802=EDGE_LOOP('',(#801));
#803=FACE_BOUND('',#802,.T.);
#804=ADVANCED_FACE('F306',(#800,#803),#797,.F.);
#805=CARTESIAN_POINT('',(49.1744,0.,0.));
#806=DIRECTION('',(1.,0.,0.));
#807=DIRECTION('',(0.,0.,-1.));
#808=AXIS2_PLACEMENT_3D('',#805,#806,#807);
#809=CYLINDRICAL_SURFACE('',#808,2.01929999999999);
#810=CARTESIAN_POINT('',(20.381918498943,0.,0.));
#811=DIRECTION('',(1.,0.,0.));
#812=DIRECTION('',(0.,0.,-1.));
#813=AXIS2_PLACEMENT_3D('',#810,#811,#812);
#814=CIRCLE('',#813,2.01929999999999);
#815=CARTESIAN_POINT('',(20.381918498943,0.,-2.01929999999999));
#816=VERTEX_POINT('',#815);
#817=EDGE_CURVE('E158',#816,#816,#814,.T.);
#818=ORIENTED_EDGE('',*,*,#817,.T.);
#819=EDGE_LOOP('',(#818));
#820=FACE_BOUND('',#819,.T.);
#821=ORIENTED_EDGE('',*,*,#714,.F.);
#822=EDGE_LOOP('',(#821));
#823=FACE_BOUND('',#822,.T.);
#824=ADVANCED_FACE('F301',(#820,#823),#809,.F.);
#825=CARTESIAN_POINT('',(20.5994,0.,0.));
#826=DIRECTION('',(1.,0.,0.));
#827=DIRECTION('',(0.,0.,-1.));
#828=AXIS2_PLACEMENT_3D('',#825,#826,#827);
#829=CONICAL_SURFACE('',#828,2.38124999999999,1.02974425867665);
#830=ORIENTED_EDGE('',*,*,#346,.T.);
#831=EDGE_LOOP('',(#830));
#832=FACE_BOUND('',#831,.T.);
#833=ORIENTED_EDGE('',*,*,#817,.F.);
#834=EDGE_LOOP('',(#833));
#835=FACE_BOUND('',#834,.T.);
#836=ADVANCED_FACE('F179',(#832,#835),#829,.F.);
#837=CARTESIAN_POINT('',(0.,0.,0.));
#838=DIRECTION('',(-1.,0.,0.));
#839=DIRECTION('',(0.,0.,1.));
#840=AXIS2_PLACEMENT_3D('',#837,#838,#839);
#841=CYLINDRICAL_SURFACE('',#840,4.3688);
#842=ORIENTED_EDGE('',*,*,#302,.T.);
#843=ORIENTED_EDGE('',*,*,#251,.T.);
#844=ORIENTED_EDGE('',*,*,#125,.T.);
#845=ORIENTED_EDGE('',*,*,#257,.T.);
#846=ORIENTED_EDGE('',*,*,#328,.T.);
#847=ORIENTED_EDGE('',*,*,#228,.T.);
#848=ORIENTED_EDGE('',*,*,#210,.T.);
#849=ORIENTED_EDGE('',*,*,#239,.T.);
#850=EDGE_LOOP('',(#842,#843,#844,#845,#846,#847,#848,#849));
#851=FACE_BOUND('',#850,.T.);
#852=CARTESIAN_POINT('',(26.9494,0.,0.));
#853=DIRECTION('',(-1.,0.,0.));
#854=DIRECTION('',(0.,0.,1.));
#855=AXIS2_PLACEMENT_3D('',#852,#853,#854);
#856=CIRCLE('',#855,4.3688);
#857=CARTESIAN_POINT('',(26.9494,0.,4.3688));
#858=VERTEX_POINT('',#857);
#859=EDGE_CURVE('E368',#858,#858,#856,.T.);
#860=ORIENTED_EDGE('',*,*,#859,.T.);
#861=EDGE_LOOP('',(#860));
#862=FACE_BOUND('',#861,.T.);
#863=CARTESIAN_POINT('',(42.2402,0.,0.));
#864=DIRECTION('',(-1.,0.,0.));
#865=DIRECTION('',(0.,0.,1.));
#866=AXIS2_PLACEMENT_3D('',#863,#864,#865);
#867=CIRCLE('',#866,4.3688);
#868=CARTESIAN_POINT('',(42.2402,0.,4.3688));
#869=VERTEX_POINT('',#868);
#870=EDGE_CURVE('E371',#869,#869,#867,.T.);
#871=ORIENTED_EDGE('',*,*,#870,.F.);
#872=EDGE_LOOP('',(#871));
#873=FACE_BOUND('',#872,.T.);
#874=CARTESIAN_POINT('',(37.7444,0.,-4.3688));
#875=CARTESIAN_POINT('',(37.7443994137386,-0.0952612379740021,-4.36879941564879));
#876=CARTESIAN_POINT('',(37.7411650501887,-0.190531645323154,-4.36567764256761));
#877=CARTESIAN_POINT('',(37.7282943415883,-0.380272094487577,-4.35325789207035));
#878=CARTESIAN_POINT('',(37.7186547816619,-0.474741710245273,-4.34395681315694));
#879=CARTESIAN_POINT('',(37.6931507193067,-0.6621972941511,-4.31935799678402));
#880=CARTESIAN_POINT('',(37.6772765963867,-0.755180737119,-4.30405099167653));
#881=CARTESIAN_POINT('',(37.6396217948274,-0.938830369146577,-4.26776212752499));
#882=CARTESIAN_POINT('',(37.617838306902,-1.02949543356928,-4.24677756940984));
#883=CARTESIAN_POINT('',(37.5445553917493,-1.2957356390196,-4.17623316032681));
#884=CARTESIAN_POINT('',(37.4849025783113,-1.46711011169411,-4.11886891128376));
#885=CARTESIAN_POINT('',(37.3474150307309,-1.7949445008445,-3.98697179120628));
#886=CARTESIAN_POINT('',(37.269579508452,-1.95140377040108,-3.91243817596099));
#887=CARTESIAN_POINT('',(37.0641544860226,-2.30906169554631,-3.71637735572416));
#888=CARTESIAN_POINT('',(36.9292336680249,-2.50240013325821,-3.58809547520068));
#889=CARTESIAN_POINT('',(36.7106806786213,-2.76800022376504,-3.38190238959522));
#890=CARTESIAN_POINT('',(36.6349816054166,-2.8525974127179,-3.31073399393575));
#891=CARTESIAN_POINT('',(36.4788277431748,-3.01383776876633,-3.16464954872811));
#892=CARTESIAN_POINT('',(36.3983732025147,-3.09048135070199,-3.08973369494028));
#893=CARTESIAN_POINT('',(36.2048052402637,-3.26108386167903,-2.91064991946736));
#894=CARTESIAN_POINT('',(36.0900022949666,-3.35189145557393,-2.80530855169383));
#895=CARTESIAN_POINT('',(35.8536916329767,-3.51997611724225,-2.59127275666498));
#896=CARTESIAN_POINT('',(35.7321795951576,-3.59724432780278,-2.48257618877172));
#897=CARTESIAN_POINT('',(35.4829438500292,-3.73854520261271,-2.26419595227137));
#898=CARTESIAN_POINT('',(35.3552297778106,-3.80259763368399,-2.15451401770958));
#899=CARTESIAN_POINT('',(35.0928531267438,-3.91788740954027,-1.93691172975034));
#900=CARTESIAN_POINT('',(34.9581973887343,-3.96913709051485,-1.82898977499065));
#901=CARTESIAN_POINT('',(34.725708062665,-4.04389130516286,-1.65503370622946));
#902=CARTESIAN_POINT('',(34.6305135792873,-4.07095567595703,-1.58700074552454));
#903=CARTESIAN_POINT('',(34.4342148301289,-4.11910696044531,-1.45742495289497));
#904=CARTESIAN_POINT('',(34.3331136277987,-4.1401969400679,-1.39587880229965));
#905=CARTESIAN_POINT('',(34.1554266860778,-4.17010165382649,-1.30317535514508));
#906=CARTESIAN_POINT('',(34.0810121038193,-4.1806937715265,-1.26852340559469));
#907=CARTESIAN_POINT('',(33.9277526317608,-4.19811016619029,-1.20964089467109));
#908=CARTESIAN_POINT('',(33.8489222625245,-4.20494607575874,-1.18537821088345));
#909=CARTESIAN_POINT('',(33.7047037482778,-4.21317606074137,-1.1557497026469));
#910=CARTESIAN_POINT('',(33.6399878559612,-4.21541388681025,-1.1474772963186));
#911=CARTESIAN_POINT('',(33.5101247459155,-4.21686093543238,-1.14215041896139));
#912=CARTESIAN_POINT('',(33.4449782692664,-4.2160744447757,-1.1450800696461));
#913=CARTESIAN_POINT('',(33.3023793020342,-4.2110869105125,-1.16329729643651));
#914=CARTESIAN_POINT('',(33.2252867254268,-4.20618920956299,-1.18110237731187));
#915=CARTESIAN_POINT('',(33.0748906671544,-4.19267074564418,-1.22821392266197));
#916=CARTESIAN_POINT('',(33.0016080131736,-4.18403152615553,-1.25757733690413));
#917=CARTESIAN_POINT('',(32.8370498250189,-4.16046913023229,-1.33376743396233));
#918=CARTESIAN_POINT('',(32.7471764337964,-4.14443032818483,-1.38318745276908));
#919=CARTESIAN_POINT('',(32.5724515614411,-4.10766807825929,-1.48883722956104));
#920=CARTESIAN_POINT('',(32.4876117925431,-4.08693420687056,-1.54508200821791));
#921=CARTESIAN_POINT('',(32.3212937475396,-4.04096112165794,-1.66162525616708));
#922=CARTESIAN_POINT('',(32.2398379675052,-4.01569633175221,-1.72194545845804));
#923=CARTESIAN_POINT('',(32.0800509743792,-3.96088264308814,-1.84454323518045));
#924=CARTESIAN_POINT('',(32.001717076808,-3.93133753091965,-1.90681904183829));
#925=CARTESIAN_POINT('',(31.7883652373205,-3.84362384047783,-2.08047481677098));
#926=CARTESIAN_POINT('',(31.6560013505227,-3.78089469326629,-2.19284658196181));
#927=CARTESIAN_POINT('',(31.397918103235,-3.64173739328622,-2.4169459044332));
#928=CARTESIAN_POINT('',(31.2722041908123,-3.56529822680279,-2.52867286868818));
#929=CARTESIAN_POINT('',(31.0281189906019,-3.39858389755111,-2.74863703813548));
#930=CARTESIAN_POINT('',(30.9097204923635,-3.30836496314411,-2.8568863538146));
#931=CARTESIAN_POINT('',(30.6806688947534,-3.11341177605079,-3.06818219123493));
#932=CARTESIAN_POINT('',(30.570010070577,-3.00868842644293,-3.17123254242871));
#933=CARTESIAN_POINT('',(30.3267496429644,-2.75133802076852,-3.3991295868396));
#934=CARTESIAN_POINT('',(30.1971537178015,-2.59364532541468,-3.52157433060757));
#935=CARTESIAN_POINT('',(29.9577084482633,-2.25263289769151,-3.74886178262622));
#936=CARTESIAN_POINT('',(29.8478365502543,-2.06934286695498,-3.85372458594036));
#937=CARTESIAN_POINT('',(29.6716951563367,-1.71422874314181,-4.02230639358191));
#938=CARTESIAN_POINT('',(29.6011223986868,-1.54650468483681,-4.09004581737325));
#939=CARTESIAN_POINT('',(29.5110064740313,-1.28465785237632,-4.17666784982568));
#940=CARTESIAN_POINT('',(29.4835867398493,-1.19564154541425,-4.20304880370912));
#941=CARTESIAN_POINT('',(29.4344347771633,-1.01465754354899,-4.25036658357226));
#942=CARTESIAN_POINT('',(29.4127000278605,-0.922691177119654,-4.27130582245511));
#943=CARTESIAN_POINT('',(29.3751779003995,-0.735703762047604,-4.30746917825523));
#944=CARTESIAN_POINT('',(29.3594361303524,-0.640665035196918,-4.32264946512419));
#945=CARTESIAN_POINT('',(29.3344607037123,-0.448989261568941,-4.34673962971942));
#946=CARTESIAN_POINT('',(29.3252240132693,-0.352352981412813,-4.35565243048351));
#947=CARTESIAN_POINT('',(29.3134519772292,-0.158305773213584,-4.36701238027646));
#948=CARTESIAN_POINT('',(29.3109157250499,-0.0608949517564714,-4.36946040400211));
#949=CARTESIAN_POINT('',(29.312599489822,0.133807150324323,-4.36783537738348));
#950=CARTESIAN_POINT('',(29.3168189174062,0.231098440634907,-4.36376289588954));
#951=CARTESIAN_POINT('',(29.3310691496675,0.413795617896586,-4.35001264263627));
#952=CARTESIAN_POINT('',(29.3403940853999,0.499309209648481,-4.34101574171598));
#953=CARTESIAN_POINT('',(29.3641253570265,0.668975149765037,-4.31812771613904));
#954=CARTESIAN_POINT('',(29.3785333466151,0.753127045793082,-4.30423499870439));
#955=CARTESIAN_POINT('',(29.4290497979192,1.00267901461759,-4.25554865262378));
#956=CARTESIAN_POINT('',(29.4724626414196,1.16532121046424,-4.21373531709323));
#957=CARTESIAN_POINT('',(29.5784884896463,1.48635070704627,-4.11178838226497));
#958=CARTESIAN_POINT('',(29.64184051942,1.64426173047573,-4.05095033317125));
#959=CARTESIAN_POINT('',(29.7839194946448,1.94621924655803,-3.91485785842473));
#960=CARTESIAN_POINT('',(29.8626516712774,2.09026099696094,-3.83959852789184));
#961=CARTESIAN_POINT('',(30.0786551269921,2.43751959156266,-3.63383287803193));
#962=CARTESIAN_POINT('',(30.2245945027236,2.63074407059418,-3.49542378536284));
#963=CARTESIAN_POINT('',(30.4597845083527,2.89448989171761,-3.27438859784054));
#964=CARTESIAN_POINT('',(30.5410883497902,2.97820935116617,-3.19829398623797));
#965=CARTESIAN_POINT('',(30.7084893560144,3.13714640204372,-3.04254552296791));
#966=CARTESIAN_POINT('',(30.794585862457,3.21236515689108,-2.96289216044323));
#967=CARTESIAN_POINT('',(30.9985372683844,3.37667907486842,-2.77568609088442));
#968=CARTESIAN_POINT('',(31.117922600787,3.46278578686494,-2.66717979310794));
#969=CARTESIAN_POINT('',(31.3634116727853,3.62131961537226,-2.44761291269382));
#970=CARTESIAN_POINT('',(31.4895211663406,3.69373476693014,-2.33655019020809));
#971=CARTESIAN_POINT('',(31.7481871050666,3.82509253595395,-2.11461708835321));
#972=CARTESIAN_POINT('',(31.8807275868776,3.88406663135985,-2.00374687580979));
#973=CARTESIAN_POINT('',(32.0855541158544,3.9626628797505,-1.84048351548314));
#974=CARTESIAN_POINT('',(32.1547928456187,3.98720677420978,-1.78659796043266));
#975=CARTESIAN_POINT('',(32.2957288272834,4.03299263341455,-1.6806855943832));
#976=CARTESIAN_POINT('',(32.3674253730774,4.05423553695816,-1.62865825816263));
#977=CARTESIAN_POINT('',(32.5262601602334,4.09663441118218,-1.51920650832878));
#978=CARTESIAN_POINT('',(32.6139628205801,4.11717103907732,-1.46235247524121));
#979=CARTESIAN_POINT('',(32.795063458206,4.15323363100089,-1.35652326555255));
#980=CARTESIAN_POINT('',(32.8884531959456,4.1687666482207,-1.30753704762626));
#981=CARTESIAN_POINT('',(33.0520981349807,4.18999233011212,-1.23745182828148));
#982=CARTESIAN_POINT('',(33.1204118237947,4.19724336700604,-1.21242591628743));
#983=CARTESIAN_POINT('',(33.2601986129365,4.20846689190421,-1.17288093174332));
#984=CARTESIAN_POINT('',(33.331660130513,4.21245048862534,-1.15832627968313));
#985=CARTESIAN_POINT('',(33.47711967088,4.21672492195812,-1.14268569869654));
#986=CARTESIAN_POINT('',(33.5511376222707,4.216971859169,-1.1417598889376));
#987=CARTESIAN_POINT('',(33.6979183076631,4.21361799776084,-1.15406422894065));
#988=CARTESIAN_POINT('',(33.7706787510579,4.21001080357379,-1.16731790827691));
#989=CARTESIAN_POINT('',(33.936633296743,4.19763421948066,-1.21116542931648));
#990=CARTESIAN_POINT('',(34.0285218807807,4.18754174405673,-1.24607641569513));
#991=CARTESIAN_POINT('',(34.2064344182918,4.16243899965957,-1.32753495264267));
#992=CARTESIAN_POINT('',(34.2924245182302,4.14740281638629,-1.37414350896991));
#993=CARTESIAN_POINT('',(34.5025310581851,4.1042688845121,-1.49922761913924));
#994=CARTESIAN_POINT('',(34.6235929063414,4.0734268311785,-1.58179027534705));
#995=CARTESIAN_POINT('',(34.858734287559,4.00277598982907,-1.75296641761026));
#996=CARTESIAN_POINT('',(34.9727993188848,3.96294932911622,-1.84159171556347));
#997=CARTESIAN_POINT('',(35.1958733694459,3.87435789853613,-2.02134359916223));
#998=CARTESIAN_POINT('',(35.3048689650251,3.82557092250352,-2.11247590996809));
#999=CARTESIAN_POINT('',(35.5181569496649,3.71907165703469,-2.29479332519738));
#1000=CARTESIAN_POINT('',(35.6224532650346,3.6613670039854,-2.38597831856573));
#1001=CARTESIAN_POINT('',(35.8331580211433,3.53276905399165,-2.57286315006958));
#1002=CARTESIAN_POINT('',(35.9392743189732,3.46126797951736,-2.66847836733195));
#1003=CARTESIAN_POINT('',(36.1461709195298,3.30754258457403,-2.85681414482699));
#1004=CARTESIAN_POINT('',(36.2469492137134,3.22531426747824,-2.94953361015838));
#1005=CARTESIAN_POINT('',(36.5397416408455,2.96243923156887,-3.22079453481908));
#1006=CARTESIAN_POINT('',(36.7231449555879,2.7650463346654,-3.39327964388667));
#1007=CARTESIAN_POINT('',(37.0037785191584,2.39427617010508,-3.65898235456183));
#1008=CARTESIAN_POINT('',(37.1098895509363,2.23314211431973,-3.75998884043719));
#1009=CARTESIAN_POINT('',(37.3023148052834,1.88976625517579,-3.94372977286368));
#1010=CARTESIAN_POINT('',(37.388643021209,1.70753950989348,-4.02647713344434));
#1011=CARTESIAN_POINT('',(37.5248814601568,1.35390616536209,-4.15730052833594));
#1012=CARTESIAN_POINT('',(37.5783529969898,1.18515634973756,-4.20875379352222));
#1013=CARTESIAN_POINT('',(37.6427048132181,0.924795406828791,-4.27073154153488));
#1014=CARTESIAN_POINT('',(37.6615060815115,0.836859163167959,-4.28885056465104));
#1015=CARTESIAN_POINT('',(37.6935489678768,0.659069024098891,-4.31974122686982));
#1016=CARTESIAN_POINT('',(37.706793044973,0.569215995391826,-4.33251523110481));
#1017=CARTESIAN_POINT('',(37.7261772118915,0.399605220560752,-4.3512148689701));
#1018=CARTESIAN_POINT('',(37.7330005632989,0.319996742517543,-4.35779907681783));
#1019=CARTESIAN_POINT('',(37.7421127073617,0.160261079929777,-4.36659237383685));
#1020=CARTESIAN_POINT('',(37.7444004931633,0.0801337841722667,-4.36880049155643));
#1021=CARTESIAN_POINT('',(37.7444,0.,-4.3688));
#1022=B_SPLINE_CURVE_WITH_KNOTS('',3,(#874,#875,#876,#877,#878,#879,#880,#881,#882,#883,#884,
#885,#886,#887,#888,#889,#890,#891,#892,#893,#894,#895,#896,#897,#898,#899,#900,#901,#902,#903,
#904,#905,#906,#907,#908,#909,#910,#911,#912,#913,#914,#915,#916,#917,#918,#919,#920,#921,#922,
#923,#924,#925,#926,#927,#928,#929,#930,#931,#932,#933,#934,#935,#936,#937,#938,#939,#940,#941,
#942,#943,#944,#945,#946,#947,#948,#949,#950,#951,#952,#953,#954,#955,#956,#957,#958,#959,#960,
#961,#962,#963,#964,#965,#966,#967,#968,#969,#970,#971,#972,#973,#974,#975,#976,#977,#978,#979,
#980,#981,#982,#983,#984,#985,#986,#987,#988,#989,#990,#991,#992,#993,#994,#995,#996,#997,#998,
#999,#1000,#1001,#1002,#1003,#1004,#1005,#1006,#1007,#1008,#1009,#1010,#1011,#1012,#1013,#1014,
#1015,#1016,#1017,#1018,#1019,#1020,#1021),.UNSPECIFIED.,.T.,.F.,(4,2,2,2,2,2,2,2,2,2,2,2,2,2,2,
2,2,2,2,2,2,2,2,2,2,2,2,2,2,2,2,2,2,2,2,2,2,2,2,2,2,2,2,2,2,2,2,2,2,2,2,2,2,2,2,2,2,2,2,2,2,2,2,
2,2,2,2,2,2,2,2,2,2,4),(0.,0.285694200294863,0.571531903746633,0.857812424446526,
1.14422928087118,1.71237367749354,2.28054270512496,3.08099703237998,3.48269083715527,
3.88436368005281,4.42464332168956,4.96527509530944,5.50509228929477,6.04438731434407,
6.40441343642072,6.76425446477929,7.01202702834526,7.25902787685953,7.45392456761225,
7.6485451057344,7.88493846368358,8.12251144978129,8.43318741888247,8.74456000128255,
9.05774895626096,9.37066252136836,9.9238159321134,10.4774157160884,11.0288140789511,
11.5798001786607,12.2913866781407,13.0021542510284,13.5820860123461,13.8721992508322,
14.162183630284,14.4543327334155,14.7463454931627,15.0383187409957,15.3302665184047,
15.5894268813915,15.8486716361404,16.3667261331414,16.9068458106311,17.4471495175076,
18.2789049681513,18.6965941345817,19.1142260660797,19.6621060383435,20.2104626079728,
20.7575214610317,21.0307528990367,21.303906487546,21.6231452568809,21.9419320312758,
22.1606385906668,22.3785984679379,22.5991170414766,22.8200021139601,23.1147684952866,
23.4111053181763,23.8593651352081,24.3085246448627,24.7588126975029,25.2087172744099,
25.6874205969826,26.1663027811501,27.1199913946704,27.7711688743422,28.4218843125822,
28.9723695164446,29.2472713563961,29.5220514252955,29.7623241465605,30.0026502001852),.UNSPECIFIED.);
#1023=CARTESIAN_POINT('',(37.7444,0.,-4.3688));
#1024=VERTEX_POINT('',#1023);
#1025=EDGE_CURVE('E200',#1024,#1024,#1022,.T.);
#1026=ORIENTED_EDGE('',*,*,#1025,.T.);
#1027=EDGE_LOOP('',(#1026));
#1028=FACE_BOUND('',#1027,.T.);
#1029=ADVANCED_FACE('F173',(#851,#862,#873,#1028),#841,.F.);
#1030=CARTESIAN_POINT('',(26.9494,0.,0.));
#1031=DIRECTION('',(1.,0.,0.));
#1032=DIRECTION('',(0.,0.,-1.));
#1033=AXIS2_PLACEMENT_3D('',#1030,#1031,#1032);
#1034=PLANE('',#1033);
#1035=ORIENTED_EDGE('',*,*,#859,.F.);
#1036=EDGE_LOOP('',(#1035));
#1037=FACE_BOUND('',#1036,.T.);
#1038=ORIENTED_EDGE('',*,*,#357,.T.);
#1039=EDGE_LOOP('',(#1038));
#1040=FACE_BOUND('',#1039,.T.);
#1041=ADVANCED_FACE('F178',(#1037,#1040),#1034,.T.);
#1042=CARTESIAN_POINT('',(49.1744,0.,0.));
#1043=DIRECTION('',(1.,0.,0.));
#1044=DIRECTION('',(0.,0.,-1.));
#1045=AXIS2_PLACEMENT_3D('',#1042,#1043,#1044);
#1046=CONICAL_SURFACE('',#1045,5.0292,0.0523598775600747);
#1047=CARTESIAN_POINT('',(42.2401999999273,0.,0.));
#1048=DIRECTION('',(-1.,0.,0.));
#1049=DIRECTION('',(0.,0.,1.));
#1050=AXIS2_PLACEMENT_3D('',#1047,#1048,#1049);
#1051=CIRCLE('',#1050,4.66579397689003);
#1052=CARTESIAN_POINT('',(42.2401999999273,0.,4.66579397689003));
#1053=VERTEX_POINT('',#1052);
#1054=EDGE_CURVE('E374',#1053,#1053,#1051,.T.);
#1055=ORIENTED_EDGE('',*,*,#1054,.T.);
#1056=EDGE_LOOP('',(#1055));
#1057=FACE_BOUND('',#1056,.T.);
#1058=ORIENTED_EDGE('',*,*,#42,.F.);
#1059=EDGE_LOOP('',(#1058));
#1060=FACE_BOUND('',#1059,.T.);
#1061=ADVANCED_FACE('F378',(#1057,#1060),#1046,.F.);
#1062=CARTESIAN_POINT('',(42.2401999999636,4.3688,0.));
#1063=DIRECTION('',(1.,0.,0.));
#1064=DIRECTION('',(0.,0.,-1.));
#1065=AXIS2_PLACEMENT_3D('',#1062,#1063,#1064);
#1066=PLANE('',#1065);
#1067=ORIENTED_EDGE('',*,*,#870,.T.);
#1068=EDGE_LOOP('',(#1067));
#1069=FACE_BOUND('',#1068,.T.);
#1070=ORIENTED_EDGE('',*,*,#1054,.F.);
#1071=EDGE_LOOP('',(#1070));
#1072=FACE_BOUND('',#1071,.T.);
#1073=ADVANCED_FACE('F180',(#1069,#1072),#1066,.T.);
#1074=CARTESIAN_POINT('',(33.528,0.,-4.7625));
#1075=DIRECTION('',(0.,0.,1.));
#1076=DIRECTION('',(1.,0.,0.));
#1077=AXIS2_PLACEMENT_3D('',#1074,#1075,#1076);
#1078=CONICAL_SURFACE('',#1077,4.2164,1.02974425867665);
#1079=CARTESIAN_POINT('',(33.528,0.,-7.29596871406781));
#1080=VERTEX_POINT('',#1079);
#1081=VERTEX_LOOP('',#1080);
#1082=FACE_BOUND('',#1081,.T.);
#1083=CARTESIAN_POINT('',(33.528,0.,-4.7625));
#1084=DIRECTION('',(0.,0.,1.));
#1085=DIRECTION('',(1.,0.,0.));
#1086=AXIS2_PLACEMENT_3D('',#1083,#1084,#1085);
#1087=CIRCLE('',#1086,4.2164);
#1088=CARTESIAN_POINT('',(37.7444,0.,-4.7625));
#1089=VERTEX_POINT('',#1088);
#1090=EDGE_CURVE('E263',#1089,#1089,#1087,.T.);
#1091=ORIENTED_EDGE('',*,*,#1090,.T.);
#1092=EDGE_LOOP('',(#1091));
#1093=FACE_BOUND('',#1092,.T.);
#1094=ADVANCED_FACE('F212',(#1082,#1093),#1078,.F.);
#1095=ORIENTED_EDGE('',*,*,#1090,.F.);
#1096=EDGE_LOOP('',(#1095));
#1097=FACE_BOUND('',#1096,.T.);
#1098=ORIENTED_EDGE('',*,*,#1025,.F.);
#1099=EDGE_LOOP('',(#1098));
#1100=FACE_BOUND('',#1099,.T.);
#1101=ADVANCED_FACE('F210',(#1097,#1100),#51,.F.);
#1102=CLOSED_SHELL('',(#46,#136,#216,#244,#262,#333,#361,#415,#446,#477,#519,#550,#572,#597,
#611,#623,#740,#760,#772,#792,#804,#824,#836,#1029,#1041,#1061,#1073,#1094,#1101));
#1103=MANIFOLD_SOLID_BREP('B2',#1102);
#1104=ADVANCED_BREP_SHAPE_REPRESENTATION('',(#18,#1103),#14);
#1105=SHAPE_DEFINITION_REPRESENTATION(#9,#1104);
ENDSEC;
END-ISO-10303-21;
